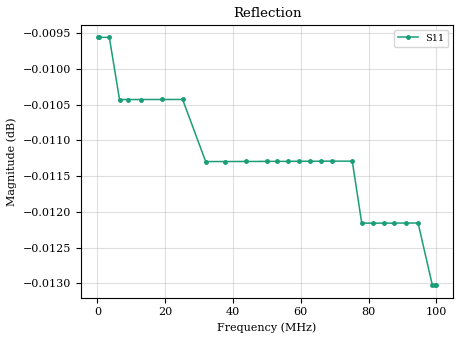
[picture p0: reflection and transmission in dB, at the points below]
! ListType=Lin
!!SAA-2 male open 0.1 to 100MHz 500 points
# MHz S RI R 50
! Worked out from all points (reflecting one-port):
!   500 points, 100 kHz to 100 MHz, reference 50 ohm
!   lowest |S11| = 0.0 dB at 100 MHz (marker M1)
!   phase of S11 starts at 0 deg and turns -0 deg over the sweep
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0.1  0.9989 4.06e-05
0.5004008  0.9989 3.09e-05
3.503407  0.9989 -3.96e-05
6.506413  0.9988 -0.000106
8.908818  0.9988 -0.000155
12.71263  0.9988 -0.00023
19.11904  0.9988 -0.000355
25.12505  0.9988 -0.000472
31.93186  0.9987 -0.000605
37.73768  0.9987 -0.000718
43.74369  0.9987 -0.000836
50.1501  0.9987 -0.000961
52.95291  0.9987 -0.00102
56.15611  0.9987 -0.00108
59.35932  0.9987 -0.00113
62.56253  0.9987 -0.00119
65.96593  0.9987 -0.00125
69.16914  0.9987 -0.0013
75.17515  0.9987 -0.00139
77.97796  0.9986 -0.00143
81.38136  0.9986 -0.00148
84.58457  0.9986 -0.00152
87.58758  0.9986 -0.00156
90.99098  0.9986 -0.0016
94.59459  0.9986 -0.00165
98.7988  0.9985 -0.00169
99.5996  0.9985 -0.0017
100  0.9985 -0.0017
